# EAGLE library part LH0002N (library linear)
BUFFER

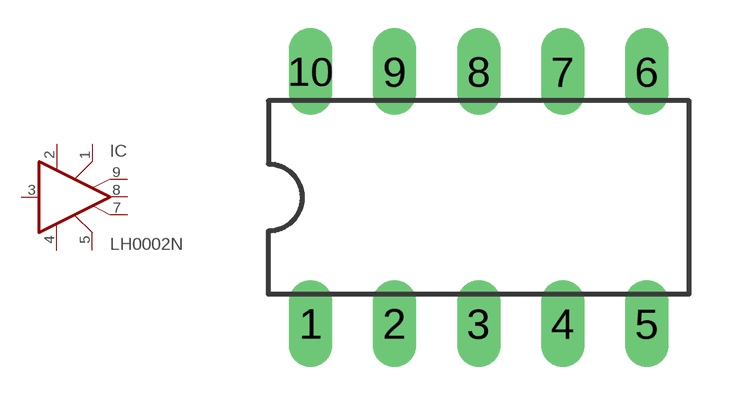
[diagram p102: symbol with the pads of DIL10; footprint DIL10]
Designator prefix IC

## LH0002N  [DIL10]
1  V2+  in
2  V1+  in
3  IN  in
4  V1-  in
5  V2-  in
7  E4
8  OUT  out
9  E3

## Footprint DIL10 (pad centres in mm)
Dual In Line Package
drill 0.813 long: 1 -5.08,-3.81; 2 -2.54,-3.81; 3 0,-3.81; 4 2.54,-3.81; 5 5.08,-3.81; 6 5.08,3.81; 7 2.54,3.81; 8 0,3.81; 9 -2.54,3.81; 10 -5.08,3.81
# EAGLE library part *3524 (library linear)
PULSE WIDTH MODULATOR

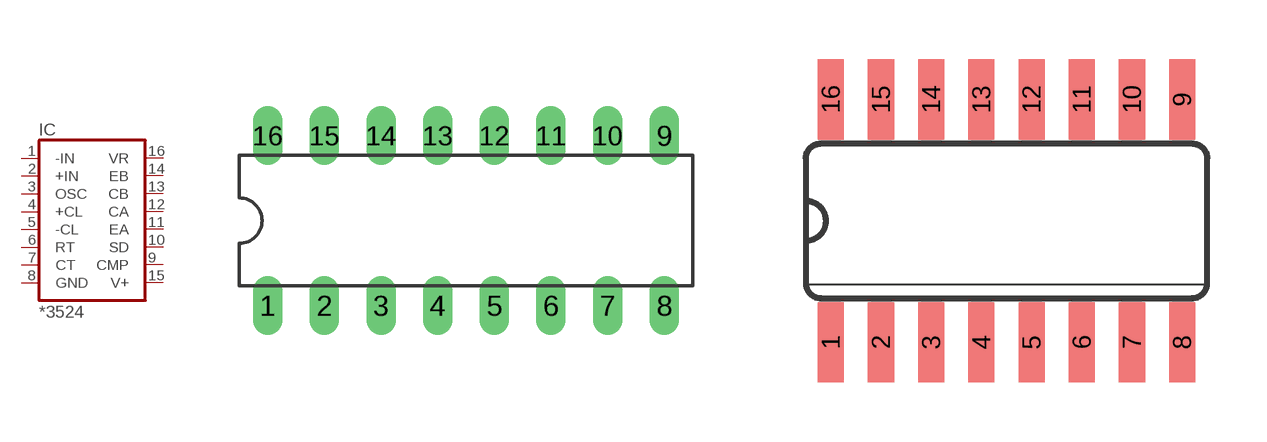
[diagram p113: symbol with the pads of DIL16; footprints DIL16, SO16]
Designator prefix IC

## LM3524N  [DIL16]
1  -IN  in
2  +IN  in
3  OSC  out
4  +CL  in
5  -CL  in
6  RT  pas
7  CT  pas
8  GND  pwr
9  CMP  pas
10  SD  in
11  EA
12  CA
13  CB
14  EB
15  V+  pwr
16  VR  out

## LM3524D  [SO16]
Pads as for DIL16

## Footprint DIL16 (pad centres in mm)
Dual In Line Package
drill 0.813 long: 1 -8.89,-3.81; 2 -6.35,-3.81; 3 -3.81,-3.81; 4 -1.27,-3.81; 5 1.27,-3.81; 6 3.81,-3.81; 7 6.35,-3.81; 8 8.89,-3.81; 9 8.89,3.81; 10 6.35,3.81; 11 3.81,3.81; 12 1.27,3.81; 13 -1.27,3.81; 14 -3.81,3.81; 15 -6.35,3.81; 16 -8.89,3.81

## Footprint SO16 (pad centres in mm)
Small Outline Package 16
smd 0.66 x 2.032: 1 -4.445,-3.073; 2 -3.175,-3.073; 3 -1.905,-3.073; 4 -0.635,-3.073; 5 0.635,-3.073; 6 1.905,-3.073; 7 3.175,-3.073; 8 4.445,-3.073; 9 4.445,3.073; 10 3.175,3.073; 11 1.905,3.073; 12 0.635,3.073; 13 -0.635,3.073; 14 -1.905,3.073; 15 -3.175,3.073; 16 -4.445,3.073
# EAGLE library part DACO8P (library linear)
8-bit DIGITAL/ANALOG CONVERTER

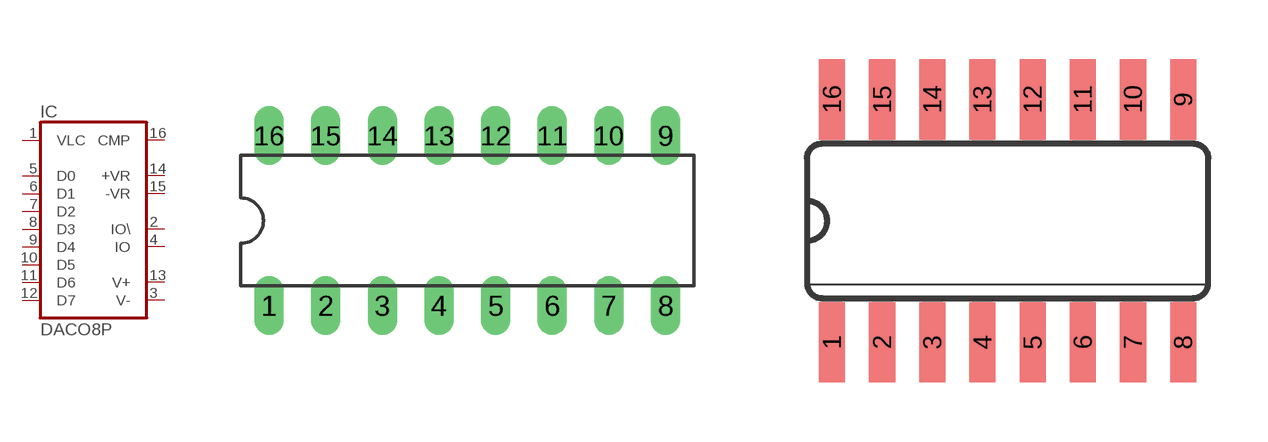
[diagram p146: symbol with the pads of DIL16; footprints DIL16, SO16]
Designator prefix IC

## DACO8PN  [DIL16]
1  VLC  in
2  IO\  out
3  V-  pwr
4  IO  out
5  D0  in
6  D1  in
7  D2  in
8  D3  in
9  D4  in
10  D5  in
11  D6  in
12  D7  in
13  V+  pwr
14  +VR  in
15  -VR  in
16  CMP  pas

## DACO8PD  [SO16]
Pads as for DIL16

## Footprint DIL16 (pad centres in mm)
Dual In Line Package
drill 0.813 long: 1 -8.89,-3.81; 2 -6.35,-3.81; 3 -3.81,-3.81; 4 -1.27,-3.81; 5 1.27,-3.81; 6 3.81,-3.81; 7 6.35,-3.81; 8 8.89,-3.81; 9 8.89,3.81; 10 6.35,3.81; 11 3.81,3.81; 12 1.27,3.81; 13 -1.27,3.81; 14 -3.81,3.81; 15 -6.35,3.81; 16 -8.89,3.81

## Footprint SO16 (pad centres in mm)
Small Outline Package 16
smd 0.66 x 2.032: 1 -4.445,-3.073; 2 -3.175,-3.073; 3 -1.905,-3.073; 4 -0.635,-3.073; 5 0.635,-3.073; 6 1.905,-3.073; 7 3.175,-3.073; 8 4.445,-3.073; 9 4.445,3.073; 10 3.175,3.073; 11 1.905,3.073; 12 0.635,3.073; 13 -0.635,3.073; 14 -1.905,3.073; 15 -3.175,3.073; 16 -4.445,3.073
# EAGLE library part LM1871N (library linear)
RC TRANSMITTER 4 channels

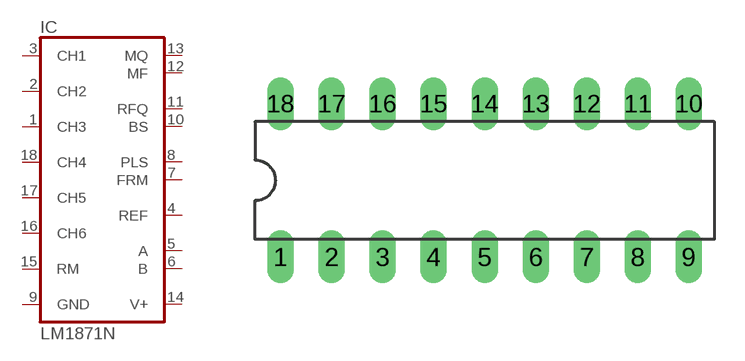
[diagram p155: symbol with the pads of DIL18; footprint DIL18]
Designator prefix IC

## LM1871N  [DIL18]
1  CH3  out
2  CH2  out
3  CH1  out
4  REF  out
5  A  in
6  B  in
7  FRM  in
8  PLS  in
9  GND  pwr
10  BS  in
11  RFQ  out
12  MF  in
13  MQ  out
14  V+  pwr
15  RM  in
16  CH6  out
17  CH5  out
18  CH4  out

## Footprint DIL18 (pad centres in mm)
Dual In Line Package
drill 0.813 long: 1 -10.16,-3.81; 2 -7.62,-3.81; 3 -5.08,-3.81; 4 -2.54,-3.81; 5 0,-3.81; 6 2.54,-3.81; 7 5.08,-3.81; 8 7.62,-3.81; 9 10.16,-3.81; 10 10.16,3.81; 11 7.62,3.81; 12 5.08,3.81; 13 2.54,3.81; 14 0,3.81; 15 -2.54,3.81; 16 -5.08,3.81; 17 -7.62,3.81; 18 -10.16,3.81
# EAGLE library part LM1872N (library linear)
RC RECEIVER 4 channels

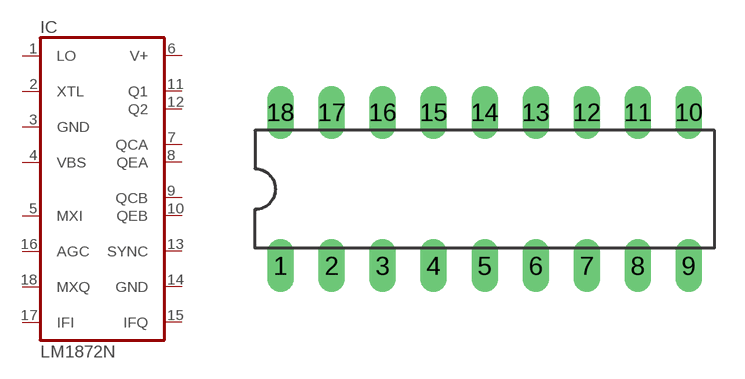
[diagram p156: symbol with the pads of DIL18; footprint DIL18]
Designator prefix IC

## LM1872N  [DIL18]
1  LO  in
2  XTL  in
3  GND  in
4  VBS  in
5  MXI  in
6  V+  in
7  QCA  out
8  QEA  out
9  QCB  out
10  QEB  out
11  Q1  out
12  Q2  out
13  SYNC  in
14  GND  in
15  IFQ  out
16  AGC  pas
17  IFI  in
18  MXQ  out

## Footprint DIL18 (pad centres in mm)
Dual In Line Package
drill 0.813 long: 1 -10.16,-3.81; 2 -7.62,-3.81; 3 -5.08,-3.81; 4 -2.54,-3.81; 5 0,-3.81; 6 2.54,-3.81; 7 5.08,-3.81; 8 7.62,-3.81; 9 10.16,-3.81; 10 10.16,3.81; 11 7.62,3.81; 12 5.08,3.81; 13 2.54,3.81; 14 0,3.81; 15 -2.54,3.81; 16 -5.08,3.81; 17 -7.62,3.81; 18 -10.16,3.81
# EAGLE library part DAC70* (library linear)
16-bit DIGITAL/ANALOG CONVERTER

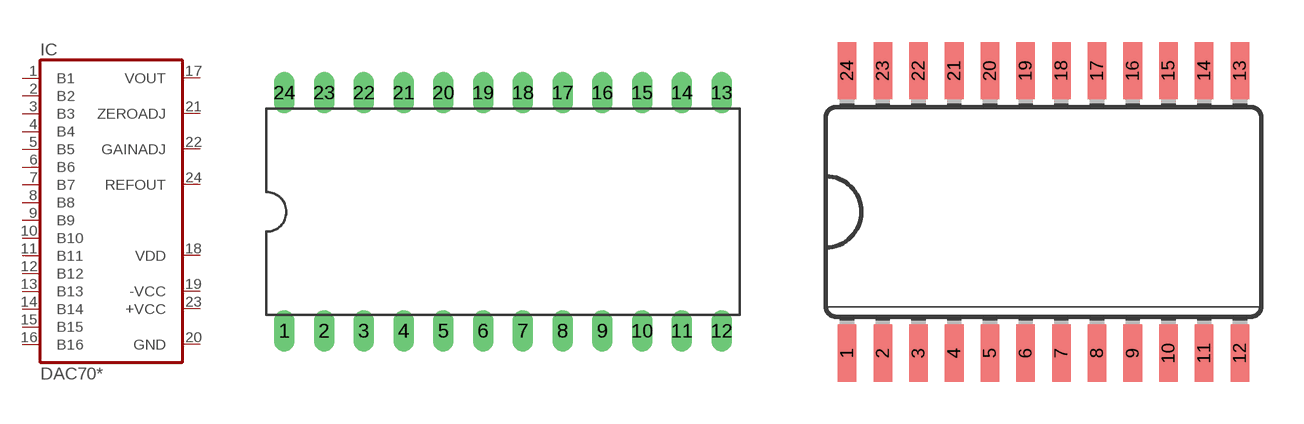
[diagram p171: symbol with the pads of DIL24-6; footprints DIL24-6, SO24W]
Designator prefix IC

## DAC701N, DAC703N  [DIL24-6]
1  B1  in
2  B2  in
3  B3  in
4  B4  in
5  B5  in
6  B6  in
7  B7  in
8  B8  in
9  B9  in
10  B10  in
11  B11  in
12  B12  in
13  B13  in
14  B14  in
15  B15  in
16  B16  in
17  VOUT  out
18  VDD  pwr
19  -VCC  pwr
20  GND  pwr
21  ZEROADJ  out
22  GAINADJ  out
23  +VCC  pwr
24  REFOUT  out

## DAC70D  [SO24W]
Pads as for DIL24-6

## Footprint DIL24-6 (pad centres in mm)
Dual In Line Package 0.6 inch
drill 0.813 long: 1 -13.97,-7.62; 2 -11.43,-7.62; 3 -8.89,-7.62; 4 -6.35,-7.62; 5 -3.81,-7.62; 6 -1.27,-7.62; 7 1.27,-7.62; 8 3.81,-7.62; 9 6.35,-7.62; 10 8.89,-7.62; 11 11.43,-7.62; 12 13.97,-7.62; 13 13.97,7.62; 14 11.43,7.62; 15 8.89,7.62; 16 6.35,7.62; 17 3.81,7.62; 18 1.27,7.62; 19 -1.27,7.62; 20 -3.81,7.62; 21 -6.35,7.62; 22 -8.89,7.62; 23 -11.43,7.62; 24 -13.97,7.62

## Footprint SO24W (pad centres in mm)
Small Outline Package 24 wide
smd 0.66 x 2.032: 1 -6.985,-5.029; 2 -5.715,-5.029; 3 -4.445,-5.029; 4 -3.175,-5.029; 5 -1.905,-5.029; 6 -0.635,-5.029; 7 0.635,-5.029; 8 1.905,-5.029; 9 3.175,-5.029; 10 4.445,-5.029; 11 5.715,-5.029; 12 6.985,-5.029; 13 6.985,5.029; 14 5.715,5.029; 15 4.445,5.029; 16 3.175,5.029; 17 1.905,5.029; 18 0.635,5.029; 19 -0.635,5.029; 20 -1.905,5.029; 21 -3.175,5.029; 22 -4.445,5.029; 23 -5.715,5.029; 24 -6.985,5.029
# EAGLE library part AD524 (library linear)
OP AMP

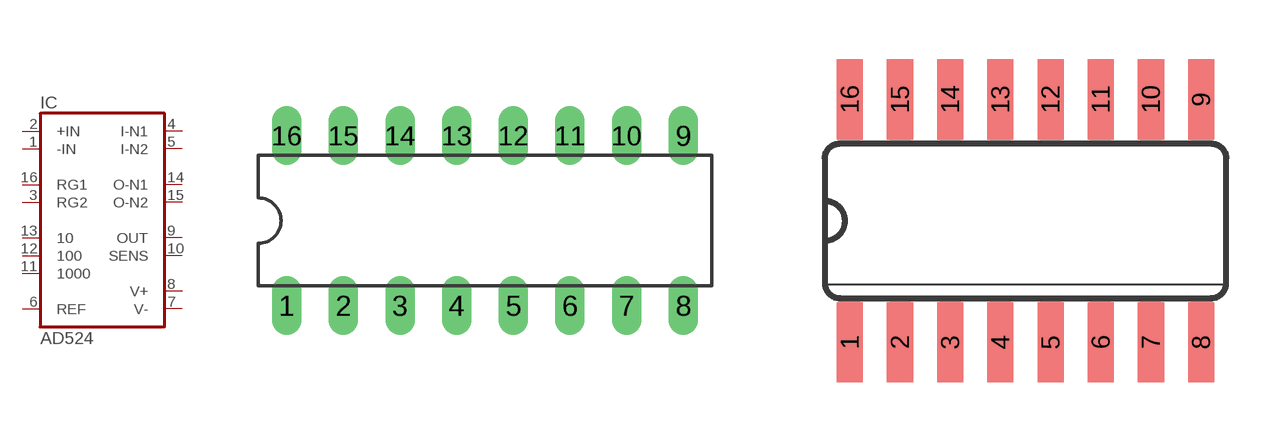
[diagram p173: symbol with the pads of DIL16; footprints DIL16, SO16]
Designator prefix IC

## AD524N  [DIL16]
1  -IN  in
2  +IN  in
3  RG2  pas
4  I-N1  in
5  I-N2  in
6  REF  in
7  V-  pwr
8  V+  pwr
9  OUT  out
10  SENS  in
11  1000  out
12  100  out
13  10  out
14  O-N1  in
15  O-N2  in
16  RG1  pas

## AD524D  [SO16]
Pads as for DIL16

## Footprint DIL16 (pad centres in mm)
Dual In Line Package
drill 0.813 long: 1 -8.89,-3.81; 2 -6.35,-3.81; 3 -3.81,-3.81; 4 -1.27,-3.81; 5 1.27,-3.81; 6 3.81,-3.81; 7 6.35,-3.81; 8 8.89,-3.81; 9 8.89,3.81; 10 6.35,3.81; 11 3.81,3.81; 12 1.27,3.81; 13 -1.27,3.81; 14 -3.81,3.81; 15 -6.35,3.81; 16 -8.89,3.81

## Footprint SO16 (pad centres in mm)
Small Outline Package 16
smd 0.66 x 2.032: 1 -4.445,-3.073; 2 -3.175,-3.073; 3 -1.905,-3.073; 4 -0.635,-3.073; 5 0.635,-3.073; 6 1.905,-3.073; 7 3.175,-3.073; 8 4.445,-3.073; 9 4.445,3.073; 10 3.175,3.073; 11 1.905,3.073; 12 0.635,3.073; 13 -0.635,3.073; 14 -1.905,3.073; 15 -3.175,3.073; 16 -4.445,3.073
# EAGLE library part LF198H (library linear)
SAMPLE&HOLD AMPLIFIER

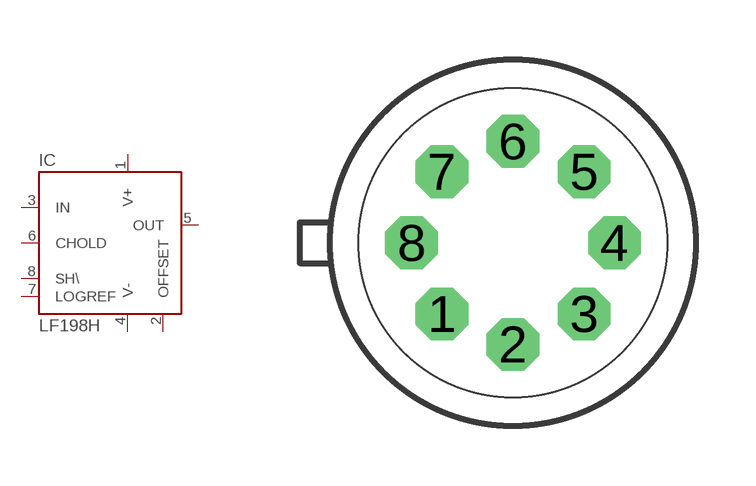
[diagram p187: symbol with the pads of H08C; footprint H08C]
Designator prefix IC

## LF198H  [H08C]
1  V+  pwr
2  OFFSET  in
3  IN  in
4  V-  pwr
5  OUT  out
6  CHOLD  pas
7  LOGREF  pwr
8  SH\  in

## Footprint H08C (pad centres in mm)
TO-99 National Semiconductor H08C Motorola MOT 601-04
drill 0.813 octagon: 1 -1.778,-1.778; 2 0,-2.54; 3 1.778,-1.778; 4 2.54,0; 5 1.778,1.778; 6 0,2.54; 7 -1.778,1.778; 8 -2.54,0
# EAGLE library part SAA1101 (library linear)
Universal sync generator (USG) Philips Semiconductors

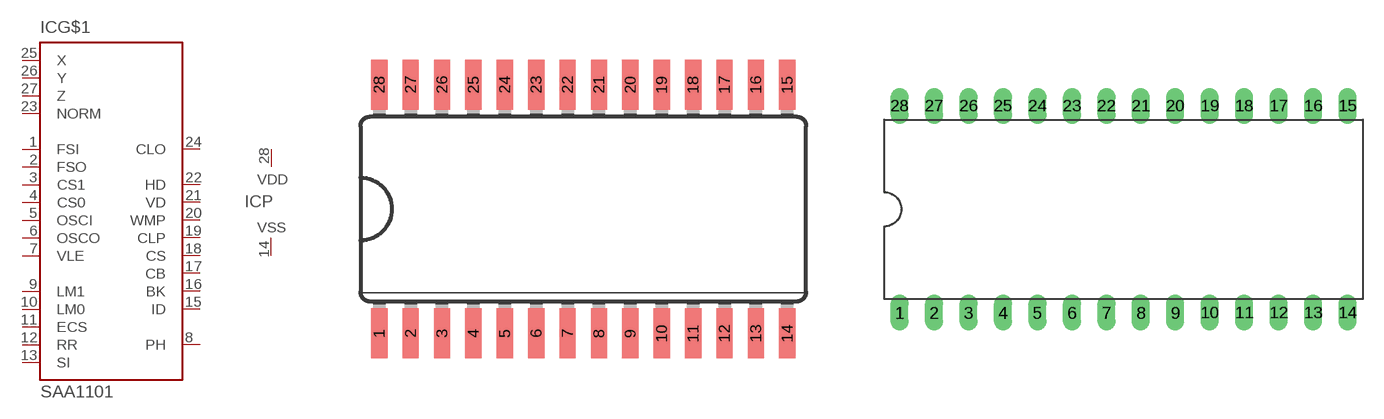
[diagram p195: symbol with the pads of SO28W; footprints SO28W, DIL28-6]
Designator prefix IC; gates G$1=SAA1101 P=VDDVSS

## SAA1101T  [SO28W]
1  G$1:FSI  in
2  G$1:FSO  out
3  G$1:CS1  in
4  G$1:CS0  in
5  G$1:OSCI  in
6  G$1:OSCO  out
7  G$1:VLE  in
8  G$1:PH  hiz
9  G$1:LM1  in
10  G$1:LM0  in
11  G$1:ECS  in
12  G$1:RR  in
13  G$1:SI  in
14  P:VSS  pwr
15  G$1:ID  out
16  G$1:BK  out
17  G$1:CB  out
18  G$1:CS  out
19  G$1:CLP  out
20  G$1:WMP  pas
21  G$1:VD  out
22  G$1:HD  out
23  G$1:NORM  in
24  G$1:CLO  out
25  G$1:X  in
26  G$1:Y  in
27  G$1:Z  in
28  P:VDD  pwr

## SAA1101P  [DIL28-6]
Pads as for SO28W

## Footprint SO28W (pad centres in mm)
Small Outline Package 28 wide
smd 0.66 x 2.032: 1 -8.255,-5.029; 2 -6.985,-5.029; 3 -5.715,-5.029; 4 -4.445,-5.029; 5 -3.175,-5.029; 6 -1.905,-5.029; 7 -0.635,-5.029; 8 0.635,-5.029; 9 1.905,-5.029; 10 3.175,-5.029; 11 4.445,-5.029; 12 5.715,-5.029; 13 6.985,-5.029; 14 8.255,-5.029; 15 8.255,5.029; 16 6.985,5.029; 17 5.715,5.029; 18 4.445,5.029; 19 3.175,5.029; 20 1.905,5.029; 21 0.635,5.029; 22 -0.635,5.029; 23 -1.905,5.029; 24 -3.175,5.029; 25 -4.445,5.029; 26 -5.715,5.029; 27 -6.985,5.029; 28 -8.255,5.029

## Footprint DIL28-6 (pad centres in mm)
Dual In Line Package 0.6 inch
drill 0.813 long: 1 -16.51,-7.62; 2 -13.97,-7.62; 3 -11.43,-7.62; 4 -8.89,-7.62; 5 -6.35,-7.62; 6 -3.81,-7.62; 7 -1.27,-7.62; 8 1.27,-7.62; 9 3.81,-7.62; 10 6.35,-7.62; 11 8.89,-7.62; 12 11.43,-7.62; 13 13.97,-7.62; 14 16.51,-7.62; 15 16.51,7.62; 16 13.97,7.62; 17 11.43,7.62; 18 8.89,7.62; 19 6.35,7.62; 20 3.81,7.62; 21 1.27,7.62; 22 -1.27,7.62; 23 -3.81,7.62; 24 -6.35,7.62; 25 -8.89,7.62; 26 -11.43,7.62; 27 -13.97,7.62; 28 -16.51,7.62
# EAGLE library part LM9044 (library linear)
Lambda Sensor Interface Amplifier Source: http://cache.national.com/ds/LM/LM9044.pdf

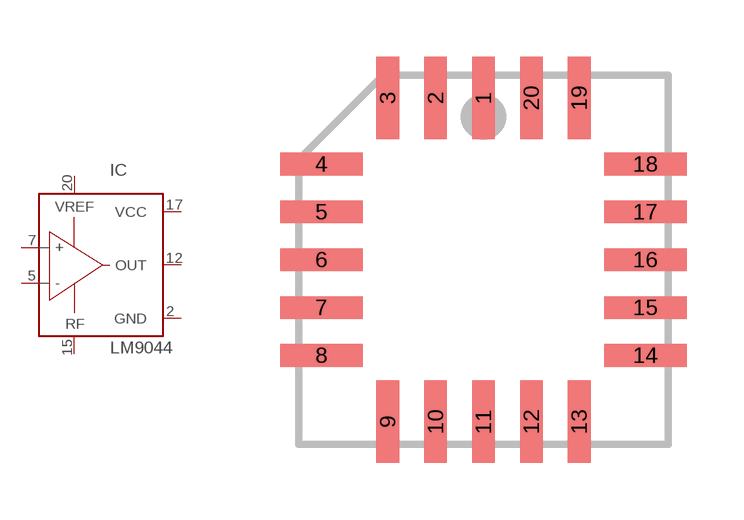
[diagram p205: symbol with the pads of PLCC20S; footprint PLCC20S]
Designator prefix IC

## LM9044V  [PLCC20S]
2  GND  pwr
5  -  in
7  +  in
12  OUT  out
15  RF  pas
17  VCC  pwr
20  VREF  pas

## Footprint PLCC20S (pad centres in mm)
PLCC 20 lead square
smd 0.6 x 2.2: 1 0,4.3; 2 -1.27,4.3; 3 -2.54,4.3; 9 -2.54,-4.3; 10 -1.27,-4.3; 11 0,-4.3; 12 1.27,-4.3; 13 2.54,-4.3; 19 2.54,4.3; 20 1.27,4.3
smd 2.2 x 0.6: 4 -4.3,2.54; 5 -4.3,1.27; 6 -4.3,0; 7 -4.3,-1.27; 8 -4.3,-2.54; 14 4.3,-2.54; 15 4.3,-1.27; 16 4.3,0; 17 4.3,1.27; 18 4.3,2.54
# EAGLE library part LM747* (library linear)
Dual Operational Amplifier Source: http://cache.national.com/ds/LM/LM747.pdf

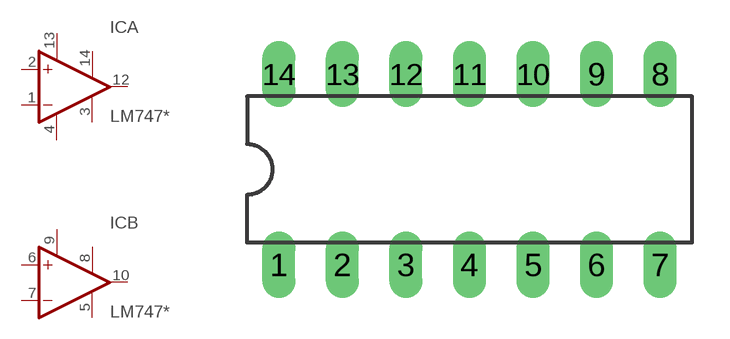
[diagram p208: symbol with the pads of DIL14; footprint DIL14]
Designator prefix IC; gates A=OPAMP-OFF+V B=OPAMP-OFF+V P=-V1

## LM747N, LM747AN, LM747CN, LM747EN  [DIL14]
1  A:-IN  in
2  A:+IN  in
3  A:NULL1  pas
4  P:V-  pwr
5  B:NULL1  pas
6  B:+IN  in
7  B:-IN  in
8  B:NULL2  pas
9  B:V+  pwr
10  B:OUT  out
12  A:OUT  out
13  A:V+  pwr
14  A:NULL2  pas

## Footprint DIL14 (pad centres in mm)
Dual In Line Package
drill 0.813 long: 1 -7.62,-3.81; 2 -5.08,-3.81; 3 -2.54,-3.81; 4 0,-3.81; 5 2.54,-3.81; 6 5.08,-3.81; 7 7.62,-3.81; 8 7.62,3.81; 9 5.08,3.81; 10 2.54,3.81; 11 0,3.81; 12 -2.54,3.81; 13 -5.08,3.81; 14 -7.62,3.81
